VERSION 5.7 ;
  NOWIREEXTENSIONATPIN ON ;
  DIVIDERCHAR "/" ;
  BUSBITCHARS "[]" ;
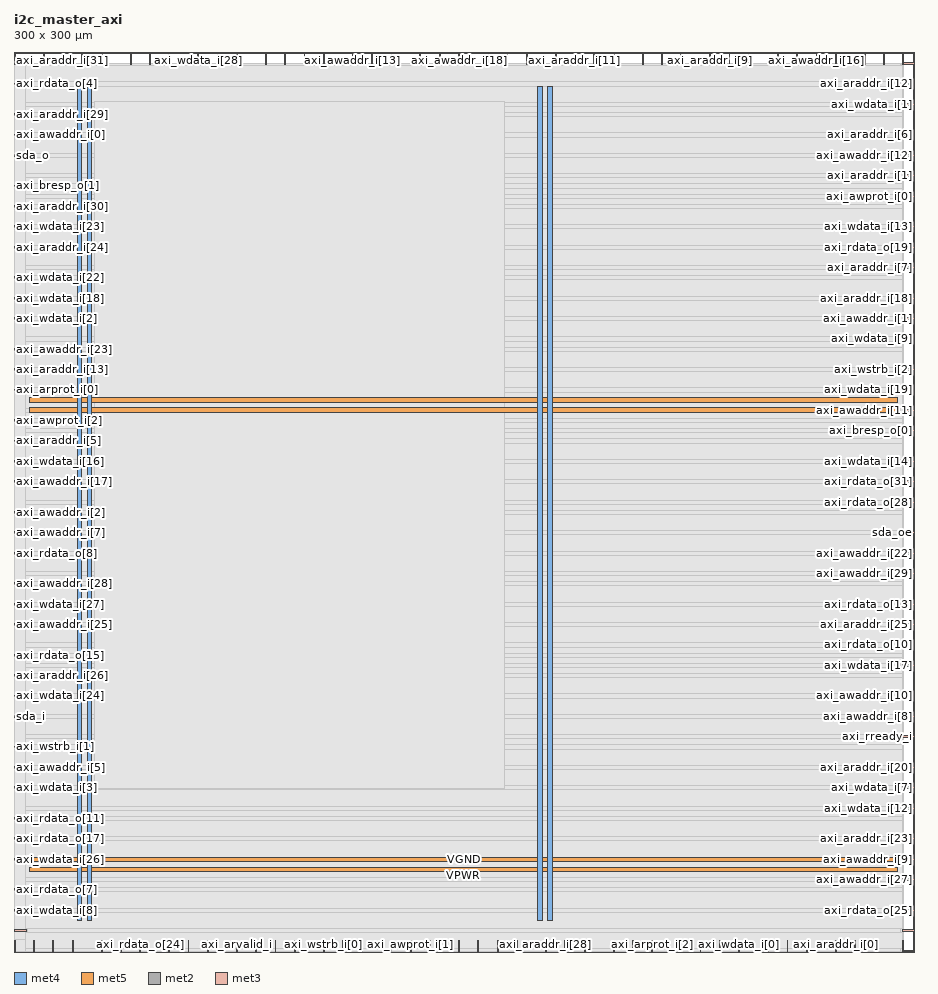
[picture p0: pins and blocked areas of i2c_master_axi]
MACRO i2c_master_axi
  CLASS BLOCK ;
  FOREIGN i2c_master_axi ;
  ORIGIN 0.000 0.000 ;
  SIZE 300.000 BY 300.000 ;
  PIN VGND
    DIRECTION INOUT ;
    USE GROUND ;
    PORT
      LAYER met4 ;
        RECT 24.340 10.640 25.940 288.560 ;
    END
    PORT
      LAYER met4 ;
        RECT 177.940 10.640 179.540 288.560 ;
    END
    PORT
      LAYER met5 ;
        RECT 5.280 30.030 294.640 31.630 ;
    END
    PORT
      LAYER met5 ;
        RECT 5.280 183.210 294.640 184.810 ;
    END
  END VGND
  PIN VPWR
    DIRECTION INOUT ;
    USE POWER ;
    PORT
      LAYER met4 ;
        RECT 21.040 10.640 22.640 288.560 ;
    END
    PORT
      LAYER met4 ;
        RECT 174.640 10.640 176.240 288.560 ;
    END
    PORT
      LAYER met5 ;
        RECT 5.280 26.730 294.640 28.330 ;
    END
    PORT
      LAYER met5 ;
        RECT 5.280 179.910 294.640 181.510 ;
    END
  END VPWR
  PIN axi_araddr_i[0]
    DIRECTION INPUT ;
    USE SIGNAL ;
    PORT
      LAYER met2 ;
        RECT 273.790 0.000 274.070 4.000 ;
    END
  END axi_araddr_i[0]
  PIN axi_araddr_i[10]
    DIRECTION INPUT ;
    USE SIGNAL ;
    PORT
      LAYER met2 ;
        RECT 235.150 0.000 235.430 4.000 ;
    END
  END axi_araddr_i[10]
  PIN axi_araddr_i[11]
    DIRECTION INPUT ;
    USE SIGNAL ;
    PORT
      LAYER met2 ;
        RECT 186.850 296.000 187.130 300.000 ;
    END
  END axi_araddr_i[11]
  PIN axi_araddr_i[12]
    DIRECTION INPUT ;
    USE SIGNAL ;
    PORT
      LAYER met3 ;
        RECT 296.000 289.040 300.000 289.640 ;
    END
  END axi_araddr_i[12]
  PIN axi_araddr_i[13]
    DIRECTION INPUT ;
    USE SIGNAL ;
    PORT
      LAYER met3 ;
        RECT 0.000 193.840 4.000 194.440 ;
    END
  END axi_araddr_i[13]
  PIN axi_araddr_i[14]
    DIRECTION INPUT ;
    USE SIGNAL ;
    PORT
      LAYER met2 ;
        RECT 180.410 296.000 180.690 300.000 ;
    END
  END axi_araddr_i[14]
  PIN axi_araddr_i[15]
    DIRECTION INPUT ;
    USE SIGNAL ;
    PORT
      LAYER met2 ;
        RECT 38.730 296.000 39.010 300.000 ;
    END
  END axi_araddr_i[15]
  PIN axi_araddr_i[16]
    DIRECTION INPUT ;
    USE SIGNAL ;
    PORT
      LAYER met2 ;
        RECT 286.670 0.000 286.950 4.000 ;
    END
  END axi_araddr_i[16]
  PIN axi_araddr_i[17]
    DIRECTION INPUT ;
    USE SIGNAL ;
    PORT
      LAYER met2 ;
        RECT 193.290 296.000 193.570 300.000 ;
    END
  END axi_araddr_i[17]
  PIN axi_araddr_i[18]
    DIRECTION INPUT ;
    USE SIGNAL ;
    PORT
      LAYER met3 ;
        RECT 296.000 217.640 300.000 218.240 ;
    END
  END axi_araddr_i[18]
  PIN axi_araddr_i[19]
    DIRECTION INPUT ;
    USE SIGNAL ;
    PORT
      LAYER met2 ;
        RECT 125.670 0.000 125.950 4.000 ;
    END
  END axi_araddr_i[19]
  PIN axi_araddr_i[1]
    DIRECTION INPUT ;
    USE SIGNAL ;
    PORT
      LAYER met3 ;
        RECT 296.000 258.440 300.000 259.040 ;
    END
  END axi_araddr_i[1]
  PIN axi_araddr_i[20]
    DIRECTION INPUT ;
    USE SIGNAL ;
    PORT
      LAYER met3 ;
        RECT 296.000 61.240 300.000 61.840 ;
    END
  END axi_araddr_i[20]
  PIN axi_araddr_i[21]
    DIRECTION INPUT ;
    USE SIGNAL ;
    PORT
      LAYER met2 ;
        RECT 9.750 296.000 10.030 300.000 ;
    END
  END axi_araddr_i[21]
  PIN axi_araddr_i[22]
    DIRECTION INPUT ;
    USE SIGNAL ;
    PORT
      LAYER met2 ;
        RECT 119.230 296.000 119.510 300.000 ;
    END
  END axi_araddr_i[22]
  PIN axi_araddr_i[23]
    DIRECTION INPUT ;
    USE SIGNAL ;
    PORT
      LAYER met3 ;
        RECT 296.000 37.440 300.000 38.040 ;
    END
  END axi_araddr_i[23]
  PIN axi_araddr_i[24]
    DIRECTION INPUT ;
    USE SIGNAL ;
    PORT
      LAYER met3 ;
        RECT 0.000 234.640 4.000 235.240 ;
    END
  END axi_araddr_i[24]
  PIN axi_araddr_i[25]
    DIRECTION INPUT ;
    USE SIGNAL ;
    PORT
      LAYER met3 ;
        RECT 296.000 108.840 300.000 109.440 ;
    END
  END axi_araddr_i[25]
  PIN axi_araddr_i[26]
    DIRECTION INPUT ;
    USE SIGNAL ;
    PORT
      LAYER met3 ;
        RECT 0.000 91.840 4.000 92.440 ;
    END
  END axi_araddr_i[26]
  PIN axi_araddr_i[27]
    DIRECTION INPUT ;
    USE SIGNAL ;
    PORT
      LAYER met2 ;
        RECT 228.710 0.000 228.990 4.000 ;
    END
  END axi_araddr_i[27]
  PIN axi_araddr_i[28]
    DIRECTION INPUT ;
    USE SIGNAL ;
    PORT
      LAYER met2 ;
        RECT 177.190 0.000 177.470 4.000 ;
    END
  END axi_araddr_i[28]
  PIN axi_araddr_i[29]
    DIRECTION INPUT ;
    USE SIGNAL ;
    PORT
      LAYER met3 ;
        RECT 0.000 278.840 4.000 279.440 ;
    END
  END axi_araddr_i[29]
  PIN axi_araddr_i[2]
    DIRECTION INPUT ;
    USE SIGNAL ;
    ANTENNAGATEAREA 0.159000 ;
    PORT
      LAYER met3 ;
        RECT 296.000 6.840 300.000 7.440 ;
    END
  END axi_araddr_i[2]
  PIN axi_araddr_i[30]
    DIRECTION INPUT ;
    USE SIGNAL ;
    PORT
      LAYER met3 ;
        RECT 0.000 248.240 4.000 248.840 ;
    END
  END axi_araddr_i[30]
  PIN axi_araddr_i[31]
    DIRECTION INPUT ;
    USE SIGNAL ;
    PORT
      LAYER met2 ;
        RECT 16.190 296.000 16.470 300.000 ;
    END
  END axi_araddr_i[31]
  PIN axi_araddr_i[3]
    DIRECTION INPUT ;
    USE SIGNAL ;
    ANTENNAGATEAREA 0.159000 ;
    PORT
      LAYER met2 ;
        RECT 199.730 0.000 200.010 4.000 ;
    END
  END axi_araddr_i[3]
  PIN axi_araddr_i[4]
    DIRECTION INPUT ;
    USE SIGNAL ;
    ANTENNAGATEAREA 0.159000 ;
    PORT
      LAYER met2 ;
        RECT 19.410 0.000 19.690 4.000 ;
    END
  END axi_araddr_i[4]
  PIN axi_araddr_i[5]
    DIRECTION INPUT ;
    USE SIGNAL ;
    PORT
      LAYER met3 ;
        RECT 0.000 170.040 4.000 170.640 ;
    END
  END axi_araddr_i[5]
  PIN axi_araddr_i[6]
    DIRECTION INPUT ;
    USE SIGNAL ;
    PORT
      LAYER met3 ;
        RECT 296.000 272.040 300.000 272.640 ;
    END
  END axi_araddr_i[6]
  PIN axi_araddr_i[7]
    DIRECTION INPUT ;
    USE SIGNAL ;
    PORT
      LAYER met3 ;
        RECT 296.000 227.840 300.000 228.440 ;
    END
  END axi_araddr_i[7]
  PIN axi_araddr_i[8]
    DIRECTION INPUT ;
    USE SIGNAL ;
    PORT
      LAYER met2 ;
        RECT 283.450 296.000 283.730 300.000 ;
    END
  END axi_araddr_i[8]
  PIN axi_araddr_i[9]
    DIRECTION INPUT ;
    USE SIGNAL ;
    PORT
      LAYER met2 ;
        RECT 231.930 296.000 232.210 300.000 ;
    END
  END axi_araddr_i[9]
  PIN axi_arprot_i[0]
    DIRECTION INPUT ;
    USE SIGNAL ;
    PORT
      LAYER met3 ;
        RECT 0.000 187.040 4.000 187.640 ;
    END
  END axi_arprot_i[0]
  PIN axi_arprot_i[1]
    DIRECTION INPUT ;
    USE SIGNAL ;
    PORT
      LAYER met2 ;
        RECT 125.670 296.000 125.950 300.000 ;
    END
  END axi_arprot_i[1]
  PIN axi_arprot_i[2]
    DIRECTION INPUT ;
    USE SIGNAL ;
    PORT
      LAYER met2 ;
        RECT 212.610 0.000 212.890 4.000 ;
    END
  END axi_arprot_i[2]
  PIN axi_arready_o
    DIRECTION OUTPUT TRISTATE ;
    USE SIGNAL ;
    ANTENNADIFFAREA 0.795200 ;
    PORT
      LAYER met2 ;
        RECT 289.890 296.000 290.170 300.000 ;
    END
  END axi_arready_o
  PIN axi_arvalid_i
    DIRECTION INPUT ;
    USE SIGNAL ;
    ANTENNAGATEAREA 0.196500 ;
    PORT
      LAYER met2 ;
        RECT 74.150 0.000 74.430 4.000 ;
    END
  END axi_arvalid_i
  PIN axi_awaddr_i[0]
    DIRECTION INPUT ;
    USE SIGNAL ;
    PORT
      LAYER met3 ;
        RECT 0.000 272.040 4.000 272.640 ;
    END
  END axi_awaddr_i[0]
  PIN axi_awaddr_i[10]
    DIRECTION INPUT ;
    USE SIGNAL ;
    PORT
      LAYER met3 ;
        RECT 296.000 85.040 300.000 85.640 ;
    END
  END axi_awaddr_i[10]
  PIN axi_awaddr_i[11]
    DIRECTION INPUT ;
    USE SIGNAL ;
    PORT
      LAYER met3 ;
        RECT 296.000 180.240 300.000 180.840 ;
    END
  END axi_awaddr_i[11]
  PIN axi_awaddr_i[12]
    DIRECTION INPUT ;
    USE SIGNAL ;
    PORT
      LAYER met3 ;
        RECT 296.000 265.240 300.000 265.840 ;
    END
  END axi_awaddr_i[12]
  PIN axi_awaddr_i[13]
    DIRECTION INPUT ;
    USE SIGNAL ;
    PORT
      LAYER met2 ;
        RECT 112.790 296.000 113.070 300.000 ;
    END
  END axi_awaddr_i[13]
  PIN axi_awaddr_i[14]
    DIRECTION INPUT ;
    USE SIGNAL ;
    PORT
      LAYER met3 ;
        RECT 0.000 6.840 4.000 7.440 ;
    END
  END axi_awaddr_i[14]
  PIN axi_awaddr_i[15]
    DIRECTION INPUT ;
    USE SIGNAL ;
    PORT
      LAYER met2 ;
        RECT 161.090 0.000 161.370 4.000 ;
    END
  END axi_awaddr_i[15]
  PIN axi_awaddr_i[16]
    DIRECTION INPUT ;
    USE SIGNAL ;
    PORT
      LAYER met2 ;
        RECT 267.350 296.000 267.630 300.000 ;
    END
  END axi_awaddr_i[16]
  PIN axi_awaddr_i[17]
    DIRECTION INPUT ;
    USE SIGNAL ;
    PORT
      LAYER met3 ;
        RECT 0.000 156.440 4.000 157.040 ;
    END
  END axi_awaddr_i[17]
  PIN axi_awaddr_i[18]
    DIRECTION INPUT ;
    USE SIGNAL ;
    PORT
      LAYER met2 ;
        RECT 148.210 296.000 148.490 300.000 ;
    END
  END axi_awaddr_i[18]
  PIN axi_awaddr_i[19]
    DIRECTION INPUT ;
    USE SIGNAL ;
    PORT
      LAYER met2 ;
        RECT 109.570 0.000 109.850 4.000 ;
    END
  END axi_awaddr_i[19]
  PIN axi_awaddr_i[1]
    DIRECTION INPUT ;
    USE SIGNAL ;
    PORT
      LAYER met3 ;
        RECT 296.000 210.840 300.000 211.440 ;
    END
  END axi_awaddr_i[1]
  PIN axi_awaddr_i[20]
    DIRECTION INPUT ;
    USE SIGNAL ;
    PORT
      LAYER met2 ;
        RECT 264.130 0.000 264.410 4.000 ;
    END
  END axi_awaddr_i[20]
  PIN axi_awaddr_i[21]
    DIRECTION INPUT ;
    USE SIGNAL ;
    PORT
      LAYER met2 ;
        RECT 222.270 0.000 222.550 4.000 ;
    END
  END axi_awaddr_i[21]
  PIN axi_awaddr_i[22]
    DIRECTION INPUT ;
    USE SIGNAL ;
    PORT
      LAYER met3 ;
        RECT 296.000 132.640 300.000 133.240 ;
    END
  END axi_awaddr_i[22]
  PIN axi_awaddr_i[23]
    DIRECTION INPUT ;
    USE SIGNAL ;
    PORT
      LAYER met3 ;
        RECT 0.000 200.640 4.000 201.240 ;
    END
  END axi_awaddr_i[23]
  PIN axi_awaddr_i[24]
    DIRECTION INPUT ;
    USE SIGNAL ;
    PORT
      LAYER met2 ;
        RECT 103.130 296.000 103.410 300.000 ;
    END
  END axi_awaddr_i[24]
  PIN axi_awaddr_i[25]
    DIRECTION INPUT ;
    USE SIGNAL ;
    PORT
      LAYER met3 ;
        RECT 0.000 108.840 4.000 109.440 ;
    END
  END axi_awaddr_i[25]
  PIN axi_awaddr_i[26]
    DIRECTION INPUT ;
    USE SIGNAL ;
    PORT
      LAYER met2 ;
        RECT 183.630 0.000 183.910 4.000 ;
    END
  END axi_awaddr_i[26]
  PIN axi_awaddr_i[27]
    DIRECTION INPUT ;
    USE SIGNAL ;
    PORT
      LAYER met3 ;
        RECT 296.000 23.840 300.000 24.440 ;
    END
  END axi_awaddr_i[27]
  PIN axi_awaddr_i[28]
    DIRECTION INPUT ;
    USE SIGNAL ;
    PORT
      LAYER met3 ;
        RECT 0.000 122.440 4.000 123.040 ;
    END
  END axi_awaddr_i[28]
  PIN axi_awaddr_i[29]
    DIRECTION INPUT ;
    USE SIGNAL ;
    PORT
      LAYER met3 ;
        RECT 296.000 125.840 300.000 126.440 ;
    END
  END axi_awaddr_i[29]
  PIN axi_awaddr_i[2]
    DIRECTION INPUT ;
    USE SIGNAL ;
    ANTENNAGATEAREA 0.213000 ;
    PORT
      LAYER met3 ;
        RECT 0.000 146.240 4.000 146.840 ;
    END
  END axi_awaddr_i[2]
  PIN axi_awaddr_i[30]
    DIRECTION INPUT ;
    USE SIGNAL ;
    PORT
      LAYER met2 ;
        RECT 80.590 0.000 80.870 4.000 ;
    END
  END axi_awaddr_i[30]
  PIN axi_awaddr_i[31]
    DIRECTION INPUT ;
    USE SIGNAL ;
    PORT
      LAYER met2 ;
        RECT 296.330 296.000 296.610 300.000 ;
    END
  END axi_awaddr_i[31]
  PIN axi_awaddr_i[3]
    DIRECTION INPUT ;
    USE SIGNAL ;
    ANTENNAGATEAREA 0.213000 ;
    PORT
      LAYER met2 ;
        RECT 251.250 0.000 251.530 4.000 ;
    END
  END axi_awaddr_i[3]
  PIN axi_awaddr_i[4]
    DIRECTION INPUT ;
    USE SIGNAL ;
    ANTENNAGATEAREA 0.213000 ;
    PORT
      LAYER met2 ;
        RECT 93.470 0.000 93.750 4.000 ;
    END
  END axi_awaddr_i[4]
  PIN axi_awaddr_i[5]
    DIRECTION INPUT ;
    USE SIGNAL ;
    PORT
      LAYER met3 ;
        RECT 0.000 61.240 4.000 61.840 ;
    END
  END axi_awaddr_i[5]
  PIN axi_awaddr_i[6]
    DIRECTION INPUT ;
    USE SIGNAL ;
    PORT
      LAYER met2 ;
        RECT 209.390 296.000 209.670 300.000 ;
    END
  END axi_awaddr_i[6]
  PIN axi_awaddr_i[7]
    DIRECTION INPUT ;
    USE SIGNAL ;
    PORT
      LAYER met3 ;
        RECT 0.000 139.440 4.000 140.040 ;
    END
  END axi_awaddr_i[7]
  PIN axi_awaddr_i[8]
    DIRECTION INPUT ;
    USE SIGNAL ;
    PORT
      LAYER met3 ;
        RECT 296.000 78.240 300.000 78.840 ;
    END
  END axi_awaddr_i[8]
  PIN axi_awaddr_i[9]
    DIRECTION INPUT ;
    USE SIGNAL ;
    PORT
      LAYER met3 ;
        RECT 296.000 30.640 300.000 31.240 ;
    END
  END axi_awaddr_i[9]
  PIN axi_awprot_i[0]
    DIRECTION INPUT ;
    USE SIGNAL ;
    PORT
      LAYER met3 ;
        RECT 296.000 251.640 300.000 252.240 ;
    END
  END axi_awprot_i[0]
  PIN axi_awprot_i[1]
    DIRECTION INPUT ;
    USE SIGNAL ;
    PORT
      LAYER met2 ;
        RECT 132.110 0.000 132.390 4.000 ;
    END
  END axi_awprot_i[1]
  PIN axi_awprot_i[2]
    DIRECTION INPUT ;
    USE SIGNAL ;
    PORT
      LAYER met3 ;
        RECT 0.000 176.840 4.000 177.440 ;
    END
  END axi_awprot_i[2]
  PIN axi_awready_o
    DIRECTION OUTPUT TRISTATE ;
    USE SIGNAL ;
    ANTENNADIFFAREA 0.795200 ;
    PORT
      LAYER met2 ;
        RECT 170.750 296.000 171.030 300.000 ;
    END
  END axi_awready_o
  PIN axi_awvalid_i
    DIRECTION INPUT ;
    USE SIGNAL ;
    ANTENNAGATEAREA 0.159000 ;
    PORT
      LAYER met2 ;
        RECT 87.030 0.000 87.310 4.000 ;
    END
  END axi_awvalid_i
  PIN axi_bready_i
    DIRECTION INPUT ;
    USE SIGNAL ;
    ANTENNAGATEAREA 0.196500 ;
    PORT
      LAYER met3 ;
        RECT 0.000 295.840 4.000 296.440 ;
    END
  END axi_bready_i
  PIN axi_bresp_o[0]
    DIRECTION OUTPUT TRISTATE ;
    USE SIGNAL ;
    PORT
      LAYER met3 ;
        RECT 296.000 173.440 300.000 174.040 ;
    END
  END axi_bresp_o[0]
  PIN axi_bresp_o[1]
    DIRECTION OUTPUT TRISTATE ;
    USE SIGNAL ;
    PORT
      LAYER met3 ;
        RECT 0.000 255.040 4.000 255.640 ;
    END
  END axi_bresp_o[1]
  PIN axi_bvalid_o
    DIRECTION OUTPUT TRISTATE ;
    USE SIGNAL ;
    ANTENNADIFFAREA 0.795200 ;
    PORT
      LAYER met2 ;
        RECT 141.770 296.000 142.050 300.000 ;
    END
  END axi_bvalid_o
  PIN axi_rdata_o[0]
    DIRECTION OUTPUT TRISTATE ;
    USE SIGNAL ;
    ANTENNADIFFAREA 0.795200 ;
    PORT
      LAYER met2 ;
        RECT 83.810 296.000 84.090 300.000 ;
    END
  END axi_rdata_o[0]
  PIN axi_rdata_o[10]
    DIRECTION OUTPUT TRISTATE ;
    USE SIGNAL ;
    ANTENNADIFFAREA 0.795200 ;
    PORT
      LAYER met3 ;
        RECT 296.000 102.040 300.000 102.640 ;
    END
  END axi_rdata_o[10]
  PIN axi_rdata_o[11]
    DIRECTION OUTPUT TRISTATE ;
    USE SIGNAL ;
    ANTENNADIFFAREA 0.795200 ;
    PORT
      LAYER met3 ;
        RECT 0.000 44.240 4.000 44.840 ;
    END
  END axi_rdata_o[11]
  PIN axi_rdata_o[12]
    DIRECTION OUTPUT TRISTATE ;
    USE SIGNAL ;
    ANTENNADIFFAREA 0.795200 ;
    PORT
      LAYER met2 ;
        RECT 273.790 296.000 274.070 300.000 ;
    END
  END axi_rdata_o[12]
  PIN axi_rdata_o[13]
    DIRECTION OUTPUT TRISTATE ;
    USE SIGNAL ;
    ANTENNADIFFAREA 0.795200 ;
    PORT
      LAYER met3 ;
        RECT 296.000 115.640 300.000 116.240 ;
    END
  END axi_rdata_o[13]
  PIN axi_rdata_o[14]
    DIRECTION OUTPUT TRISTATE ;
    USE SIGNAL ;
    ANTENNADIFFAREA 0.795200 ;
    PORT
      LAYER met2 ;
        RECT 138.550 0.000 138.830 4.000 ;
    END
  END axi_rdata_o[14]
  PIN axi_rdata_o[15]
    DIRECTION OUTPUT TRISTATE ;
    USE SIGNAL ;
    ANTENNADIFFAREA 0.795200 ;
    PORT
      LAYER met3 ;
        RECT 0.000 98.640 4.000 99.240 ;
    END
  END axi_rdata_o[15]
  PIN axi_rdata_o[16]
    DIRECTION OUTPUT TRISTATE ;
    USE SIGNAL ;
    ANTENNADIFFAREA 0.795200 ;
    PORT
      LAYER met2 ;
        RECT 199.730 296.000 200.010 300.000 ;
    END
  END axi_rdata_o[16]
  PIN axi_rdata_o[17]
    DIRECTION OUTPUT TRISTATE ;
    USE SIGNAL ;
    ANTENNADIFFAREA 0.795200 ;
    PORT
      LAYER met3 ;
        RECT 0.000 37.440 4.000 38.040 ;
    END
  END axi_rdata_o[17]
  PIN axi_rdata_o[18]
    DIRECTION OUTPUT TRISTATE ;
    USE SIGNAL ;
    ANTENNADIFFAREA 0.795200 ;
    PORT
      LAYER met2 ;
        RECT 45.170 296.000 45.450 300.000 ;
    END
  END axi_rdata_o[18]
  PIN axi_rdata_o[19]
    DIRECTION OUTPUT TRISTATE ;
    USE SIGNAL ;
    ANTENNADIFFAREA 0.445500 ;
    PORT
      LAYER met3 ;
        RECT 296.000 234.640 300.000 235.240 ;
    END
  END axi_rdata_o[19]
  PIN axi_rdata_o[1]
    DIRECTION OUTPUT TRISTATE ;
    USE SIGNAL ;
    ANTENNADIFFAREA 0.795200 ;
    PORT
      LAYER met2 ;
        RECT 74.150 296.000 74.430 300.000 ;
    END
  END axi_rdata_o[1]
  PIN axi_rdata_o[20]
    DIRECTION OUTPUT TRISTATE ;
    USE SIGNAL ;
    ANTENNADIFFAREA 0.795200 ;
    PORT
      LAYER met2 ;
        RECT 244.810 296.000 245.090 300.000 ;
    END
  END axi_rdata_o[20]
  PIN axi_rdata_o[21]
    DIRECTION OUTPUT TRISTATE ;
    USE SIGNAL ;
    ANTENNADIFFAREA 0.795200 ;
    PORT
      LAYER met2 ;
        RECT 254.470 296.000 254.750 300.000 ;
    END
  END axi_rdata_o[21]
  PIN axi_rdata_o[22]
    DIRECTION OUTPUT TRISTATE ;
    USE SIGNAL ;
    ANTENNADIFFAREA 0.795200 ;
    PORT
      LAYER met2 ;
        RECT 238.370 296.000 238.650 300.000 ;
    END
  END axi_rdata_o[22]
  PIN axi_rdata_o[23]
    DIRECTION OUTPUT TRISTATE ;
    USE SIGNAL ;
    ANTENNADIFFAREA 0.795200 ;
    PORT
      LAYER met2 ;
        RECT 6.530 0.000 6.810 4.000 ;
    END
  END axi_rdata_o[23]
  PIN axi_rdata_o[24]
    DIRECTION OUTPUT TRISTATE ;
    USE SIGNAL ;
    ANTENNADIFFAREA 0.795200 ;
    PORT
      LAYER met2 ;
        RECT 41.950 0.000 42.230 4.000 ;
    END
  END axi_rdata_o[24]
  PIN axi_rdata_o[25]
    DIRECTION OUTPUT TRISTATE ;
    USE SIGNAL ;
    ANTENNADIFFAREA 0.445500 ;
    PORT
      LAYER met3 ;
        RECT 296.000 13.640 300.000 14.240 ;
    END
  END axi_rdata_o[25]
  PIN axi_rdata_o[26]
    DIRECTION OUTPUT TRISTATE ;
    USE SIGNAL ;
    ANTENNADIFFAREA 0.795200 ;
    PORT
      LAYER met2 ;
        RECT 29.070 296.000 29.350 300.000 ;
    END
  END axi_rdata_o[26]
  PIN axi_rdata_o[27]
    DIRECTION OUTPUT TRISTATE ;
    USE SIGNAL ;
    ANTENNADIFFAREA 0.795200 ;
    PORT
      LAYER met2 ;
        RECT 96.690 296.000 96.970 300.000 ;
    END
  END axi_rdata_o[27]
  PIN axi_rdata_o[28]
    DIRECTION OUTPUT TRISTATE ;
    USE SIGNAL ;
    ANTENNADIFFAREA 0.445500 ;
    PORT
      LAYER met3 ;
        RECT 296.000 149.640 300.000 150.240 ;
    END
  END axi_rdata_o[28]
  PIN axi_rdata_o[29]
    DIRECTION OUTPUT TRISTATE ;
    USE SIGNAL ;
    ANTENNADIFFAREA 0.795200 ;
    PORT
      LAYER met2 ;
        RECT 90.250 296.000 90.530 300.000 ;
    END
  END axi_rdata_o[29]
  PIN axi_rdata_o[2]
    DIRECTION OUTPUT TRISTATE ;
    USE SIGNAL ;
    ANTENNADIFFAREA 0.795200 ;
    PORT
      LAYER met2 ;
        RECT 29.070 0.000 29.350 4.000 ;
    END
  END axi_rdata_o[2]
  PIN axi_rdata_o[30]
    DIRECTION OUTPUT TRISTATE ;
    USE SIGNAL ;
    ANTENNADIFFAREA 0.795200 ;
    PORT
      LAYER met2 ;
        RECT 22.630 296.000 22.910 300.000 ;
    END
  END axi_rdata_o[30]
  PIN axi_rdata_o[31]
    DIRECTION OUTPUT TRISTATE ;
    USE SIGNAL ;
    ANTENNADIFFAREA 0.795200 ;
    PORT
      LAYER met3 ;
        RECT 296.000 156.440 300.000 157.040 ;
    END
  END axi_rdata_o[31]
  PIN axi_rdata_o[3]
    DIRECTION OUTPUT TRISTATE ;
    USE SIGNAL ;
    ANTENNADIFFAREA 0.795200 ;
    PORT
      LAYER met2 ;
        RECT 135.330 296.000 135.610 300.000 ;
    END
  END axi_rdata_o[3]
  PIN axi_rdata_o[4]
    DIRECTION OUTPUT TRISTATE ;
    USE SIGNAL ;
    ANTENNADIFFAREA 0.795200 ;
    PORT
      LAYER met3 ;
        RECT 0.000 289.040 4.000 289.640 ;
    END
  END axi_rdata_o[4]
  PIN axi_rdata_o[5]
    DIRECTION OUTPUT TRISTATE ;
    USE SIGNAL ;
    ANTENNADIFFAREA 0.795200 ;
    PORT
      LAYER met2 ;
        RECT 296.330 0.000 296.610 4.000 ;
    END
  END axi_rdata_o[5]
  PIN axi_rdata_o[6]
    DIRECTION OUTPUT TRISTATE ;
    USE SIGNAL ;
    ANTENNADIFFAREA 0.795200 ;
    PORT
      LAYER met2 ;
        RECT 154.650 0.000 154.930 4.000 ;
    END
  END axi_rdata_o[6]
  PIN axi_rdata_o[7]
    DIRECTION OUTPUT TRISTATE ;
    USE SIGNAL ;
    ANTENNADIFFAREA 0.795200 ;
    PORT
      LAYER met3 ;
        RECT 0.000 20.440 4.000 21.040 ;
    END
  END axi_rdata_o[7]
  PIN axi_rdata_o[8]
    DIRECTION OUTPUT TRISTATE ;
    USE SIGNAL ;
    ANTENNADIFFAREA 0.795200 ;
    PORT
      LAYER met3 ;
        RECT 0.000 132.640 4.000 133.240 ;
    END
  END axi_rdata_o[8]
  PIN axi_rdata_o[9]
    DIRECTION OUTPUT TRISTATE ;
    USE SIGNAL ;
    ANTENNADIFFAREA 0.795200 ;
    PORT
      LAYER met2 ;
        RECT 64.490 0.000 64.770 4.000 ;
    END
  END axi_rdata_o[9]
  PIN axi_rready_i
    DIRECTION INPUT ;
    USE SIGNAL ;
    ANTENNAGATEAREA 0.196500 ;
    PORT
      LAYER met3 ;
        RECT 296.000 71.440 300.000 72.040 ;
    END
  END axi_rready_i
  PIN axi_rresp_o[0]
    DIRECTION OUTPUT TRISTATE ;
    USE SIGNAL ;
    PORT
      LAYER met2 ;
        RECT 190.070 0.000 190.350 4.000 ;
    END
  END axi_rresp_o[0]
  PIN axi_rresp_o[1]
    DIRECTION OUTPUT TRISTATE ;
    USE SIGNAL ;
    PORT
      LAYER met3 ;
        RECT 296.000 0.040 300.000 0.640 ;
    END
  END axi_rresp_o[1]
  PIN axi_rvalid_o
    DIRECTION OUTPUT TRISTATE ;
    USE SIGNAL ;
    ANTENNADIFFAREA 0.795200 ;
    PORT
      LAYER met2 ;
        RECT 67.710 296.000 67.990 300.000 ;
    END
  END axi_rvalid_o
  PIN axi_wdata_i[0]
    DIRECTION INPUT ;
    USE SIGNAL ;
    ANTENNAGATEAREA 0.213000 ;
    PORT
      LAYER met2 ;
        RECT 241.590 0.000 241.870 4.000 ;
    END
  END axi_wdata_i[0]
  PIN axi_wdata_i[10]
    DIRECTION INPUT ;
    USE SIGNAL ;
    ANTENNAGATEAREA 0.126000 ;
    PORT
      LAYER met2 ;
        RECT 35.510 0.000 35.790 4.000 ;
    END
  END axi_wdata_i[10]
  PIN axi_wdata_i[11]
    DIRECTION INPUT ;
    USE SIGNAL ;
    ANTENNAGATEAREA 0.126000 ;
    PORT
      LAYER met2 ;
        RECT 116.010 0.000 116.290 4.000 ;
    END
  END axi_wdata_i[11]
  PIN axi_wdata_i[12]
    DIRECTION INPUT ;
    USE SIGNAL ;
    ANTENNAGATEAREA 0.213000 ;
    PORT
      LAYER met3 ;
        RECT 296.000 47.640 300.000 48.240 ;
    END
  END axi_wdata_i[12]
  PIN axi_wdata_i[13]
    DIRECTION INPUT ;
    USE SIGNAL ;
    ANTENNAGATEAREA 0.159000 ;
    PORT
      LAYER met3 ;
        RECT 296.000 241.440 300.000 242.040 ;
    END
  END axi_wdata_i[13]
  PIN axi_wdata_i[14]
    DIRECTION INPUT ;
    USE SIGNAL ;
    ANTENNAGATEAREA 0.213000 ;
    PORT
      LAYER met3 ;
        RECT 296.000 163.240 300.000 163.840 ;
    END
  END axi_wdata_i[14]
  PIN axi_wdata_i[15]
    DIRECTION INPUT ;
    USE SIGNAL ;
    ANTENNAGATEAREA 0.213000 ;
    PORT
      LAYER met2 ;
        RECT 257.690 0.000 257.970 4.000 ;
    END
  END axi_wdata_i[15]
  PIN axi_wdata_i[16]
    DIRECTION INPUT ;
    USE SIGNAL ;
    ANTENNAGATEAREA 0.196500 ;
    PORT
      LAYER met3 ;
        RECT 0.000 163.240 4.000 163.840 ;
    END
  END axi_wdata_i[16]
  PIN axi_wdata_i[17]
    DIRECTION INPUT ;
    USE SIGNAL ;
    ANTENNAGATEAREA 0.159000 ;
    PORT
      LAYER met3 ;
        RECT 296.000 95.240 300.000 95.840 ;
    END
  END axi_wdata_i[17]
  PIN axi_wdata_i[18]
    DIRECTION INPUT ;
    USE SIGNAL ;
    ANTENNAGATEAREA 0.126000 ;
    PORT
      LAYER met3 ;
        RECT 0.000 217.640 4.000 218.240 ;
    END
  END axi_wdata_i[18]
  PIN axi_wdata_i[19]
    DIRECTION INPUT ;
    USE SIGNAL ;
    ANTENNAGATEAREA 0.213000 ;
    PORT
      LAYER met3 ;
        RECT 296.000 187.040 300.000 187.640 ;
    END
  END axi_wdata_i[19]
  PIN axi_wdata_i[1]
    DIRECTION INPUT ;
    USE SIGNAL ;
    ANTENNAGATEAREA 0.213000 ;
    PORT
      LAYER met3 ;
        RECT 296.000 282.240 300.000 282.840 ;
    END
  END axi_wdata_i[1]
  PIN axi_wdata_i[20]
    DIRECTION INPUT ;
    USE SIGNAL ;
    ANTENNAGATEAREA 0.159000 ;
    PORT
      LAYER met2 ;
        RECT 280.230 0.000 280.510 4.000 ;
    END
  END axi_wdata_i[20]
  PIN axi_wdata_i[21]
    DIRECTION INPUT ;
    USE SIGNAL ;
    ANTENNAGATEAREA 0.159000 ;
    PORT
      LAYER met3 ;
        RECT 296.000 295.840 300.000 296.440 ;
    END
  END axi_wdata_i[21]
  PIN axi_wdata_i[22]
    DIRECTION INPUT ;
    USE SIGNAL ;
    ANTENNAGATEAREA 0.213000 ;
    PORT
      LAYER met3 ;
        RECT 0.000 224.440 4.000 225.040 ;
    END
  END axi_wdata_i[22]
  PIN axi_wdata_i[23]
    DIRECTION INPUT ;
    USE SIGNAL ;
    ANTENNAGATEAREA 0.213000 ;
    PORT
      LAYER met3 ;
        RECT 0.000 241.440 4.000 242.040 ;
    END
  END axi_wdata_i[23]
  PIN axi_wdata_i[24]
    DIRECTION INPUT ;
    USE SIGNAL ;
    ANTENNAGATEAREA 0.196500 ;
    PORT
      LAYER met3 ;
        RECT 0.000 85.040 4.000 85.640 ;
    END
  END axi_wdata_i[24]
  PIN axi_wdata_i[25]
    DIRECTION INPUT ;
    USE SIGNAL ;
    ANTENNAGATEAREA 0.196500 ;
    PORT
      LAYER met2 ;
        RECT 0.090 0.000 0.370 4.000 ;
    END
  END axi_wdata_i[25]
  PIN axi_wdata_i[26]
    DIRECTION INPUT ;
    USE SIGNAL ;
    ANTENNAGATEAREA 0.196500 ;
    PORT
      LAYER met3 ;
        RECT 0.000 30.640 4.000 31.240 ;
    END
  END axi_wdata_i[26]
  PIN axi_wdata_i[27]
    DIRECTION INPUT ;
    USE SIGNAL ;
    ANTENNAGATEAREA 0.196500 ;
    PORT
      LAYER met3 ;
        RECT 0.000 115.640 4.000 116.240 ;
    END
  END axi_wdata_i[27]
  PIN axi_wdata_i[28]
    DIRECTION INPUT ;
    USE SIGNAL ;
    ANTENNAGATEAREA 0.213000 ;
    PORT
      LAYER met2 ;
        RECT 61.270 296.000 61.550 300.000 ;
    END
  END axi_wdata_i[28]
  PIN axi_wdata_i[29]
    DIRECTION INPUT ;
    USE SIGNAL ;
    ANTENNAGATEAREA 0.213000 ;
    PORT
      LAYER met2 ;
        RECT 164.310 296.000 164.590 300.000 ;
    END
  END axi_wdata_i[29]
  PIN axi_wdata_i[2]
    DIRECTION INPUT ;
    USE SIGNAL ;
    ANTENNAGATEAREA 0.213000 ;
    PORT
      LAYER met3 ;
        RECT 0.000 210.840 4.000 211.440 ;
    END
  END axi_wdata_i[2]
  PIN axi_wdata_i[30]
    DIRECTION INPUT ;
    USE SIGNAL ;
    ANTENNAGATEAREA 0.213000 ;
    PORT
      LAYER met2 ;
        RECT 51.610 0.000 51.890 4.000 ;
    END
  END axi_wdata_i[30]
  PIN axi_wdata_i[31]
    DIRECTION INPUT ;
    USE SIGNAL ;
    ANTENNAGATEAREA 0.213000 ;
    PORT
      LAYER met2 ;
        RECT 12.970 0.000 13.250 4.000 ;
    END
  END axi_wdata_i[31]
  PIN axi_wdata_i[3]
    DIRECTION INPUT ;
    USE SIGNAL ;
    ANTENNAGATEAREA 0.213000 ;
    PORT
      LAYER met3 ;
        RECT 0.000 54.440 4.000 55.040 ;
    END
  END axi_wdata_i[3]
  PIN axi_wdata_i[4]
    DIRECTION INPUT ;
    USE SIGNAL ;
    ANTENNAGATEAREA 0.213000 ;
    PORT
      LAYER met2 ;
        RECT 157.870 296.000 158.150 300.000 ;
    END
  END axi_wdata_i[4]
  PIN axi_wdata_i[5]
    DIRECTION INPUT ;
    USE SIGNAL ;
    ANTENNAGATEAREA 0.126000 ;
    PORT
      LAYER met2 ;
        RECT 148.210 0.000 148.490 4.000 ;
    END
  END axi_wdata_i[5]
  PIN axi_wdata_i[6]
    DIRECTION INPUT ;
    USE SIGNAL ;
    ANTENNAGATEAREA 0.159000 ;
    PORT
      LAYER met2 ;
        RECT 260.910 296.000 261.190 300.000 ;
    END
  END axi_wdata_i[6]
  PIN axi_wdata_i[7]
    DIRECTION INPUT ;
    USE SIGNAL ;
    ANTENNAGATEAREA 0.213000 ;
    PORT
      LAYER met3 ;
        RECT 296.000 54.440 300.000 55.040 ;
    END
  END axi_wdata_i[7]
  PIN axi_wdata_i[8]
    DIRECTION INPUT ;
    USE SIGNAL ;
    ANTENNAGATEAREA 0.126000 ;
    PORT
      LAYER met3 ;
        RECT 0.000 13.640 4.000 14.240 ;
    END
  END axi_wdata_i[8]
  PIN axi_wdata_i[9]
    DIRECTION INPUT ;
    USE SIGNAL ;
    ANTENNAGATEAREA 0.159000 ;
    PORT
      LAYER met3 ;
        RECT 296.000 204.040 300.000 204.640 ;
    END
  END axi_wdata_i[9]
  PIN axi_wready_o
    DIRECTION OUTPUT TRISTATE ;
    USE SIGNAL ;
    ANTENNADIFFAREA 0.795200 ;
    PORT
      LAYER met2 ;
        RECT 58.050 0.000 58.330 4.000 ;
    END
  END axi_wready_o
  PIN axi_wstrb_i[0]
    DIRECTION INPUT ;
    USE SIGNAL ;
    PORT
      LAYER met2 ;
        RECT 103.130 0.000 103.410 4.000 ;
    END
  END axi_wstrb_i[0]
  PIN axi_wstrb_i[1]
    DIRECTION INPUT ;
    USE SIGNAL ;
    PORT
      LAYER met3 ;
        RECT 0.000 68.040 4.000 68.640 ;
    END
  END axi_wstrb_i[1]
  PIN axi_wstrb_i[2]
    DIRECTION INPUT ;
    USE SIGNAL ;
    PORT
      LAYER met3 ;
        RECT 296.000 193.840 300.000 194.440 ;
    END
  END axi_wstrb_i[2]
  PIN axi_wstrb_i[3]
    DIRECTION INPUT ;
    USE SIGNAL ;
    PORT
      LAYER met2 ;
        RECT 167.530 0.000 167.810 4.000 ;
    END
  END axi_wstrb_i[3]
  PIN axi_wvalid_i
    DIRECTION INPUT ;
    USE SIGNAL ;
    ANTENNAGATEAREA 0.213000 ;
    PORT
      LAYER met2 ;
        RECT 222.270 296.000 222.550 300.000 ;
    END
  END axi_wvalid_i
  PIN clk_i
    DIRECTION INPUT ;
    USE SIGNAL ;
    ANTENNAGATEAREA 0.852000 ;
    PORT
      LAYER met2 ;
        RECT 215.830 296.000 216.110 300.000 ;
    END
  END clk_i
  PIN rst_ni
    DIRECTION INPUT ;
    USE SIGNAL ;
    ANTENNAGATEAREA 0.213000 ;
    PORT
      LAYER met2 ;
        RECT 0.090 296.000 0.370 300.000 ;
    END
  END rst_ni
  PIN scl_o
    DIRECTION OUTPUT TRISTATE ;
    USE SIGNAL ;
    PORT
      LAYER met2 ;
        RECT 51.610 296.000 51.890 300.000 ;
    END
  END scl_o
  PIN scl_oe
    DIRECTION OUTPUT TRISTATE ;
    USE SIGNAL ;
    ANTENNADIFFAREA 0.795200 ;
    PORT
      LAYER met2 ;
        RECT 206.170 0.000 206.450 4.000 ;
    END
  END scl_oe
  PIN sda_i
    DIRECTION INPUT ;
    USE SIGNAL ;
    ANTENNAGATEAREA 0.196500 ;
    PORT
      LAYER met3 ;
        RECT 0.000 78.240 4.000 78.840 ;
    END
  END sda_i
  PIN sda_o
    DIRECTION OUTPUT TRISTATE ;
    USE SIGNAL ;
    PORT
      LAYER met3 ;
        RECT 0.000 265.240 4.000 265.840 ;
    END
  END sda_o
  PIN sda_oe
    DIRECTION OUTPUT TRISTATE ;
    USE SIGNAL ;
    ANTENNADIFFAREA 0.445500 ;
    PORT
      LAYER met3 ;
        RECT 296.000 139.440 300.000 140.040 ;
    END
  END sda_oe
  OBS
      LAYER li1 ;
        RECT 5.520 10.795 294.400 288.405 ;
      LAYER met1 ;
        RECT 0.070 9.220 296.630 288.560 ;
      LAYER met2 ;
        RECT 0.650 295.720 9.470 296.325 ;
        RECT 10.310 295.720 15.910 296.325 ;
        RECT 16.750 295.720 22.350 296.325 ;
        RECT 23.190 295.720 28.790 296.325 ;
        RECT 29.630 295.720 38.450 296.325 ;
        RECT 39.290 295.720 44.890 296.325 ;
        RECT 45.730 295.720 51.330 296.325 ;
        RECT 52.170 295.720 60.990 296.325 ;
        RECT 61.830 295.720 67.430 296.325 ;
        RECT 68.270 295.720 73.870 296.325 ;
        RECT 74.710 295.720 83.530 296.325 ;
        RECT 84.370 295.720 89.970 296.325 ;
        RECT 90.810 295.720 96.410 296.325 ;
        RECT 97.250 295.720 102.850 296.325 ;
        RECT 103.690 295.720 112.510 296.325 ;
        RECT 113.350 295.720 118.950 296.325 ;
        RECT 119.790 295.720 125.390 296.325 ;
        RECT 126.230 295.720 135.050 296.325 ;
        RECT 135.890 295.720 141.490 296.325 ;
        RECT 142.330 295.720 147.930 296.325 ;
        RECT 148.770 295.720 157.590 296.325 ;
        RECT 158.430 295.720 164.030 296.325 ;
        RECT 164.870 295.720 170.470 296.325 ;
        RECT 171.310 295.720 180.130 296.325 ;
        RECT 180.970 295.720 186.570 296.325 ;
        RECT 187.410 295.720 193.010 296.325 ;
        RECT 193.850 295.720 199.450 296.325 ;
        RECT 200.290 295.720 209.110 296.325 ;
        RECT 209.950 295.720 215.550 296.325 ;
        RECT 216.390 295.720 221.990 296.325 ;
        RECT 222.830 295.720 231.650 296.325 ;
        RECT 232.490 295.720 238.090 296.325 ;
        RECT 238.930 295.720 244.530 296.325 ;
        RECT 245.370 295.720 254.190 296.325 ;
        RECT 255.030 295.720 260.630 296.325 ;
        RECT 261.470 295.720 267.070 296.325 ;
        RECT 267.910 295.720 273.510 296.325 ;
        RECT 274.350 295.720 283.170 296.325 ;
        RECT 284.010 295.720 289.610 296.325 ;
        RECT 290.450 295.720 296.050 296.325 ;
        RECT 0.100 4.280 296.600 295.720 ;
        RECT 0.650 0.155 6.250 4.280 ;
        RECT 7.090 0.155 12.690 4.280 ;
        RECT 13.530 0.155 19.130 4.280 ;
        RECT 19.970 0.155 28.790 4.280 ;
        RECT 29.630 0.155 35.230 4.280 ;
        RECT 36.070 0.155 41.670 4.280 ;
        RECT 42.510 0.155 51.330 4.280 ;
        RECT 52.170 0.155 57.770 4.280 ;
        RECT 58.610 0.155 64.210 4.280 ;
        RECT 65.050 0.155 73.870 4.280 ;
        RECT 74.710 0.155 80.310 4.280 ;
        RECT 81.150 0.155 86.750 4.280 ;
        RECT 87.590 0.155 93.190 4.280 ;
        RECT 94.030 0.155 102.850 4.280 ;
        RECT 103.690 0.155 109.290 4.280 ;
        RECT 110.130 0.155 115.730 4.280 ;
        RECT 116.570 0.155 125.390 4.280 ;
        RECT 126.230 0.155 131.830 4.280 ;
        RECT 132.670 0.155 138.270 4.280 ;
        RECT 139.110 0.155 147.930 4.280 ;
        RECT 148.770 0.155 154.370 4.280 ;
        RECT 155.210 0.155 160.810 4.280 ;
        RECT 161.650 0.155 167.250 4.280 ;
        RECT 168.090 0.155 176.910 4.280 ;
        RECT 177.750 0.155 183.350 4.280 ;
        RECT 184.190 0.155 189.790 4.280 ;
        RECT 190.630 0.155 199.450 4.280 ;
        RECT 200.290 0.155 205.890 4.280 ;
        RECT 206.730 0.155 212.330 4.280 ;
        RECT 213.170 0.155 221.990 4.280 ;
        RECT 222.830 0.155 228.430 4.280 ;
        RECT 229.270 0.155 234.870 4.280 ;
        RECT 235.710 0.155 241.310 4.280 ;
        RECT 242.150 0.155 250.970 4.280 ;
        RECT 251.810 0.155 257.410 4.280 ;
        RECT 258.250 0.155 263.850 4.280 ;
        RECT 264.690 0.155 273.510 4.280 ;
        RECT 274.350 0.155 279.950 4.280 ;
        RECT 280.790 0.155 286.390 4.280 ;
        RECT 287.230 0.155 296.050 4.280 ;
      LAYER met3 ;
        RECT 4.400 295.440 295.600 296.305 ;
        RECT 3.990 290.040 296.000 295.440 ;
        RECT 4.400 288.640 295.600 290.040 ;
        RECT 3.990 283.240 296.000 288.640 ;
        RECT 3.990 281.840 295.600 283.240 ;
        RECT 3.990 279.840 296.000 281.840 ;
        RECT 4.400 278.440 296.000 279.840 ;
        RECT 3.990 273.040 296.000 278.440 ;
        RECT 4.400 271.640 295.600 273.040 ;
        RECT 3.990 266.240 296.000 271.640 ;
        RECT 4.400 264.840 295.600 266.240 ;
        RECT 3.990 259.440 296.000 264.840 ;
        RECT 3.990 258.040 295.600 259.440 ;
        RECT 3.990 256.040 296.000 258.040 ;
        RECT 4.400 254.640 296.000 256.040 ;
        RECT 3.990 252.640 296.000 254.640 ;
        RECT 3.990 251.240 295.600 252.640 ;
        RECT 3.990 249.240 296.000 251.240 ;
        RECT 4.400 247.840 296.000 249.240 ;
        RECT 3.990 242.440 296.000 247.840 ;
        RECT 4.400 241.040 295.600 242.440 ;
        RECT 3.990 235.640 296.000 241.040 ;
        RECT 4.400 234.240 295.600 235.640 ;
        RECT 3.990 228.840 296.000 234.240 ;
        RECT 3.990 227.440 295.600 228.840 ;
        RECT 3.990 225.440 296.000 227.440 ;
        RECT 4.400 224.040 296.000 225.440 ;
        RECT 3.990 218.640 296.000 224.040 ;
        RECT 4.400 217.240 295.600 218.640 ;
        RECT 3.990 211.840 296.000 217.240 ;
        RECT 4.400 210.440 295.600 211.840 ;
        RECT 3.990 205.040 296.000 210.440 ;
        RECT 3.990 203.640 295.600 205.040 ;
        RECT 3.990 201.640 296.000 203.640 ;
        RECT 4.400 200.240 296.000 201.640 ;
        RECT 3.990 194.840 296.000 200.240 ;
        RECT 4.400 193.440 295.600 194.840 ;
        RECT 3.990 188.040 296.000 193.440 ;
        RECT 4.400 186.640 295.600 188.040 ;
        RECT 3.990 181.240 296.000 186.640 ;
        RECT 3.990 179.840 295.600 181.240 ;
        RECT 3.990 177.840 296.000 179.840 ;
        RECT 4.400 176.440 296.000 177.840 ;
        RECT 3.990 174.440 296.000 176.440 ;
        RECT 3.990 173.040 295.600 174.440 ;
        RECT 3.990 171.040 296.000 173.040 ;
        RECT 4.400 169.640 296.000 171.040 ;
        RECT 3.990 164.240 296.000 169.640 ;
        RECT 4.400 162.840 295.600 164.240 ;
        RECT 3.990 157.440 296.000 162.840 ;
        RECT 4.400 156.040 295.600 157.440 ;
        RECT 3.990 150.640 296.000 156.040 ;
        RECT 3.990 149.240 295.600 150.640 ;
        RECT 3.990 147.240 296.000 149.240 ;
        RECT 4.400 145.840 296.000 147.240 ;
        RECT 3.990 140.440 296.000 145.840 ;
        RECT 4.400 139.040 295.600 140.440 ;
        RECT 3.990 133.640 296.000 139.040 ;
        RECT 4.400 132.240 295.600 133.640 ;
        RECT 3.990 126.840 296.000 132.240 ;
        RECT 3.990 125.440 295.600 126.840 ;
        RECT 3.990 123.440 296.000 125.440 ;
        RECT 4.400 122.040 296.000 123.440 ;
        RECT 3.990 116.640 296.000 122.040 ;
        RECT 4.400 115.240 295.600 116.640 ;
        RECT 3.990 109.840 296.000 115.240 ;
        RECT 4.400 108.440 295.600 109.840 ;
        RECT 3.990 103.040 296.000 108.440 ;
        RECT 3.990 101.640 295.600 103.040 ;
        RECT 3.990 99.640 296.000 101.640 ;
        RECT 4.400 98.240 296.000 99.640 ;
        RECT 3.990 96.240 296.000 98.240 ;
        RECT 3.990 94.840 295.600 96.240 ;
        RECT 3.990 92.840 296.000 94.840 ;
        RECT 4.400 91.440 296.000 92.840 ;
        RECT 3.990 86.040 296.000 91.440 ;
        RECT 4.400 84.640 295.600 86.040 ;
        RECT 3.990 79.240 296.000 84.640 ;
        RECT 4.400 77.840 295.600 79.240 ;
        RECT 3.990 72.440 296.000 77.840 ;
        RECT 3.990 71.040 295.600 72.440 ;
        RECT 3.990 69.040 296.000 71.040 ;
        RECT 4.400 67.640 296.000 69.040 ;
        RECT 3.990 62.240 296.000 67.640 ;
        RECT 4.400 60.840 295.600 62.240 ;
        RECT 3.990 55.440 296.000 60.840 ;
        RECT 4.400 54.040 295.600 55.440 ;
        RECT 3.990 48.640 296.000 54.040 ;
        RECT 3.990 47.240 295.600 48.640 ;
        RECT 3.990 45.240 296.000 47.240 ;
        RECT 4.400 43.840 296.000 45.240 ;
        RECT 3.990 38.440 296.000 43.840 ;
        RECT 4.400 37.040 295.600 38.440 ;
        RECT 3.990 31.640 296.000 37.040 ;
        RECT 4.400 30.240 295.600 31.640 ;
        RECT 3.990 24.840 296.000 30.240 ;
        RECT 3.990 23.440 295.600 24.840 ;
        RECT 3.990 21.440 296.000 23.440 ;
        RECT 4.400 20.040 296.000 21.440 ;
        RECT 3.990 14.640 296.000 20.040 ;
        RECT 4.400 13.240 295.600 14.640 ;
        RECT 3.990 7.840 296.000 13.240 ;
        RECT 4.400 6.440 295.600 7.840 ;
        RECT 3.990 1.040 296.000 6.440 ;
        RECT 3.990 0.175 295.600 1.040 ;
      LAYER met4 ;
        RECT 26.975 54.575 163.465 283.385 ;
  END
END i2c_master_axi
END LIBRARY

